VERSION 5.8 ;
BUSBITCHARS "[]" ;
DIVIDERCHAR "/" ;
UNITS
  DATABASE MICRONS 1000 ;
END UNITS
MANUFACTURINGGRID 0.005 ;
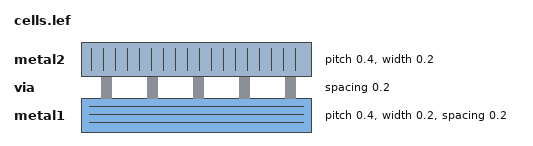
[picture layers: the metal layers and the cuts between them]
LAYER metal1
  TYPE ROUTING ;
  DIRECTION HORIZONTAL ;
  PITCH 0.4 ;
  WIDTH 0.2 ;
  SPACING 0.2 ;
  RESISTANCE RPERSQ 0.08 ;
END metal1
LAYER via
  TYPE CUT ;
  SPACING 0.2 ;
END via
LAYER metal2
  TYPE ROUTING ;
  DIRECTION VERTICAL ;
  PITCH 0.4 ;
  WIDTH 0.2 ;
END metal2
VIA M1M2 DEFAULT
  LAYER metal1 ;
    RECT -0.1 -0.1 0.1 0.1 ;
  LAYER via ;
    RECT -0.05 -0.05 0.05 0.05 ;
  LAYER metal2 ;
    RECT -0.1 -0.1 0.1 0.1 ;
END M1M2
SITE core
  CLASS CORE ;
  SIZE 0.4 BY 3.6 ;
END core
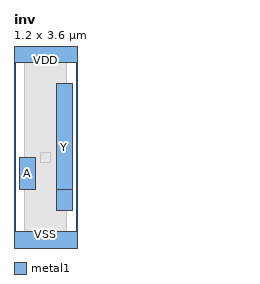
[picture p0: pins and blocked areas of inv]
MACRO inv
  CLASS CORE ;
  ORIGIN 0 0 ;
  SIZE 1.2 BY 3.6 ;
  SYMMETRY X Y ;
  SITE core ;
  PIN A
    DIRECTION INPUT ;
    USE SIGNAL ;
    PORT
      LAYER metal1 ;
        RECT 0.1 1.0 0.4 1.6 ;
    END
  END A
  PIN Y
    DIRECTION OUTPUT ;
    USE SIGNAL ;
    PORT
      LAYER metal1 ;
        RECT 0.8 0.6 1.1 3.0 ;
        POLYGON 0.8 0.6 1.1 0.6 1.1 1.0 0.8 1.0 ;
    END
  END Y
  PIN VDD
    DIRECTION INOUT ;
    USE POWER ;
    PORT
      LAYER metal1 ;
        RECT 0 3.4 1.2 3.8 ;
    END
  END VDD
  PIN VSS
    DIRECTION INOUT ;
    USE GROUND ;
    PORT
      LAYER metal1 ;
        RECT 0 -0.2 1.2 0.2 ;
    END
  END VSS
  OBS
    LAYER metal2 ;
      RECT 0.2 0.2 1.0 3.4 ;
    LAYER via ;
      RECT 0.5 1.5 0.7 1.7 ;
  END
END inv
END LIBRARY
